One B-rep face of a CAD part: STEP entity #199.
In plain terms, the planar face has unit normal (1, 0, 0).
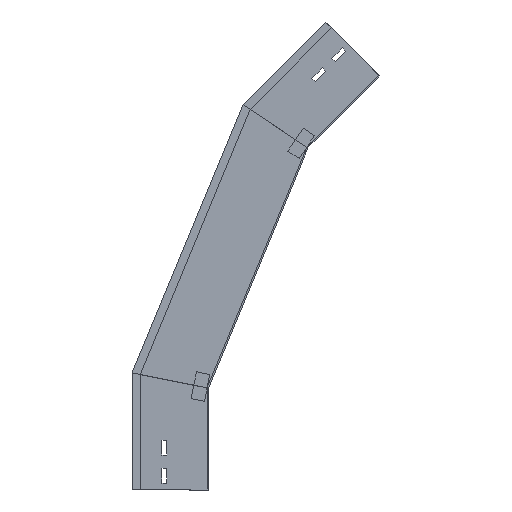
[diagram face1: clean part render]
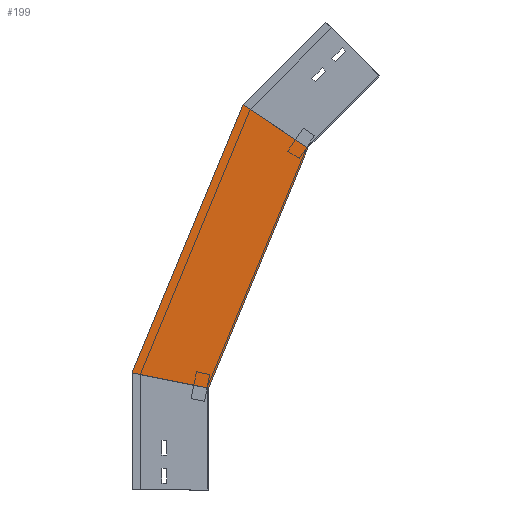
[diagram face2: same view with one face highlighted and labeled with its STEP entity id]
Its self-contained STEP definition (entity closure, numbers rounded to 3 decimals):
#45 = LINE ( 'NONE', #408, #687 ) ;
#77 = CARTESIAN_POINT ( 'NONE',  ( 0., 0., 150. ) ) ;
#149 = CARTESIAN_POINT ( 'NONE',  ( 0., -28.701, 144.291 ) ) ;
#199 = ADVANCED_FACE ( 'NONE', ( #1121 ), #878, .T. ) ;
#319 = EDGE_CURVE ( 'NONE', #1024, #534, #1294, .T. ) ;
#335 = EDGE_LOOP ( 'NONE', ( #1472, #568, #1241, #1020 ) ) ;
#384 = VECTOR ( 'NONE', #1180, 1000. ) ;
#408 = CARTESIAN_POINT ( 'NONE',  ( 0., -212.704, 459.655 ) ) ;
#416 = CARTESIAN_POINT ( 'NONE',  ( 0., 112.5, 172.378 ) ) ;
#518 = CARTESIAN_POINT ( 'NONE',  ( 0., 9.458, 127.166 ) ) ;
#534 = VERTEX_POINT ( 'NONE', #779 ) ;
#538 = VERTEX_POINT ( 'NONE', #416 ) ;
#568 = ORIENTED_EDGE ( 'NONE', *, *, #579, .T. ) ;
#579 = EDGE_CURVE ( 'NONE', #695, #534, #45, .T. ) ;
#594 = CARTESIAN_POINT ( 'NONE',  ( 0., 9.458, 127.166 ) ) ;
#687 = VECTOR ( 'NONE', #1335, 1000. ) ;
#695 = VERTEX_POINT ( 'NONE', #1018 ) ;
#779 = CARTESIAN_POINT ( 'NONE',  ( 0., -146.568, 503.846 ) ) ;
#878 = PLANE ( 'NONE',  #1494 ) ;
#884 = DIRECTION ( 'NONE',  ( 0., 0., -1. ) ) ;
#980 = LINE ( 'NONE', #149, #384 ) ;
#992 = DIRECTION ( 'NONE',  ( 1., 0., 0. ) ) ;
#1018 = CARTESIAN_POINT ( 'NONE',  ( 0., -51.195, 567.572 ) ) ;
#1020 = ORIENTED_EDGE ( 'NONE', *, *, #1291, .F. ) ;
#1024 = VERTEX_POINT ( 'NONE', #77 ) ;
#1058 = VECTOR ( 'NONE', #1427, 1000. ) ;
#1121 = FACE_OUTER_BOUND ( 'NONE', #335, .T. ) ;
#1144 = EDGE_CURVE ( 'NONE', #538, #695, #1169, .T. ) ;
#1169 = LINE ( 'NONE', #1409, #1337 ) ;
#1180 = DIRECTION ( 'NONE',  ( 0., -0.981, -0.195 ) ) ;
#1241 = ORIENTED_EDGE ( 'NONE', *, *, #319, .F. ) ;
#1291 = EDGE_CURVE ( 'NONE', #538, #1024, #980, .T. ) ;
#1294 = LINE ( 'NONE', #594, #1058 ) ;
#1335 = DIRECTION ( 'NONE',  ( 0., -0.831, -0.556 ) ) ;
#1337 = VECTOR ( 'NONE', #1415, 1000. ) ;
#1409 = CARTESIAN_POINT ( 'NONE',  ( 0., 113.395, 170.218 ) ) ;
#1415 = DIRECTION ( 'NONE',  ( 0., -0.383, 0.924 ) ) ;
#1427 = DIRECTION ( 'NONE',  ( 0., -0.383, 0.924 ) ) ;
#1472 = ORIENTED_EDGE ( 'NONE', *, *, #1144, .T. ) ;
#1494 = AXIS2_PLACEMENT_3D ( 'NONE', #518, #992, #884 ) ;
